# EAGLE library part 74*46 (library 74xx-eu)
BCD to seven segment DECODER/DRIVER, open collector

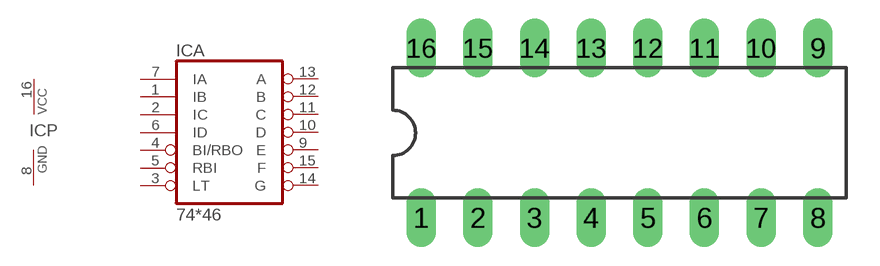
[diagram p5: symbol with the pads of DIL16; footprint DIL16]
Designator prefix IC; gates A=7446 P=PWRN

## 7446N  [DIL16]
1  A:IB  in
2  A:IC  in
3  A:LT  in
4  A:BI/RBO  in
5  A:RBI  in
6  A:ID  in
7  A:IA  in
8  P:GND  pwr
9  A:E  oc
10  A:D  oc
11  A:C  oc
12  A:B  oc
13  A:A  oc
14  A:G  oc
15  A:F  oc
16  P:VCC  pwr

## Footprint DIL16 (pad centres in mm)
Dual In Line Package
drill 0.813 long: 1 -8.89,-3.81; 2 -6.35,-3.81; 3 -3.81,-3.81; 4 -1.27,-3.81; 5 1.27,-3.81; 6 3.81,-3.81; 7 6.35,-3.81; 8 8.89,-3.81; 9 8.89,3.81; 10 6.35,3.81; 11 3.81,3.81; 12 1.27,3.81; 13 -1.27,3.81; 14 -3.81,3.81; 15 -6.35,3.81; 16 -8.89,3.81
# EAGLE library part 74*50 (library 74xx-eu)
Dual 2-wide 2-input AND OR INVERTER gate (one gate expandable)

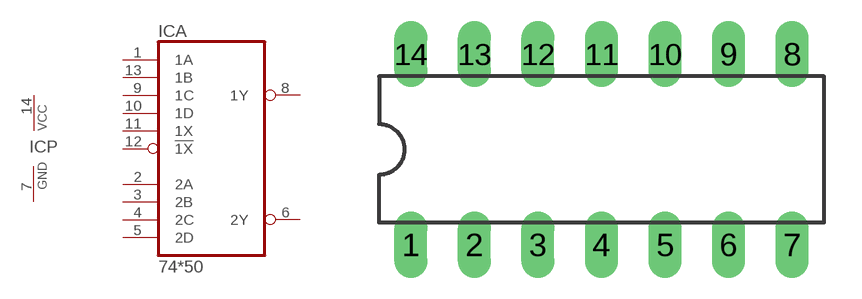
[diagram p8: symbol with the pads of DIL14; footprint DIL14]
Designator prefix IC; gates A=7450 P=PWRN

## 7450N  [DIL14]
1  A:1A  in
2  A:2A  in
3  A:2B  in
4  A:2C  in
5  A:2D  in
6  A:2Y  out
7  P:GND  pwr
8  A:1Y  out
9  A:1C  in
10  A:1D  in
11  A:1X  in
12  A:!1X  in
13  A:1B  in
14  P:VCC  pwr

## Footprint DIL14 (pad centres in mm)
Dual In Line Package
drill 0.813 long: 1 -7.62,-3.81; 2 -5.08,-3.81; 3 -2.54,-3.81; 4 0,-3.81; 5 2.54,-3.81; 6 5.08,-3.81; 7 7.62,-3.81; 8 7.62,3.81; 9 5.08,3.81; 10 2.54,3.81; 11 0,3.81; 12 -2.54,3.81; 13 -5.08,3.81; 14 -7.62,3.81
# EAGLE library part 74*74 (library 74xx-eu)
Dual D type positive edge triggered FLIP FLOP, preset and clear

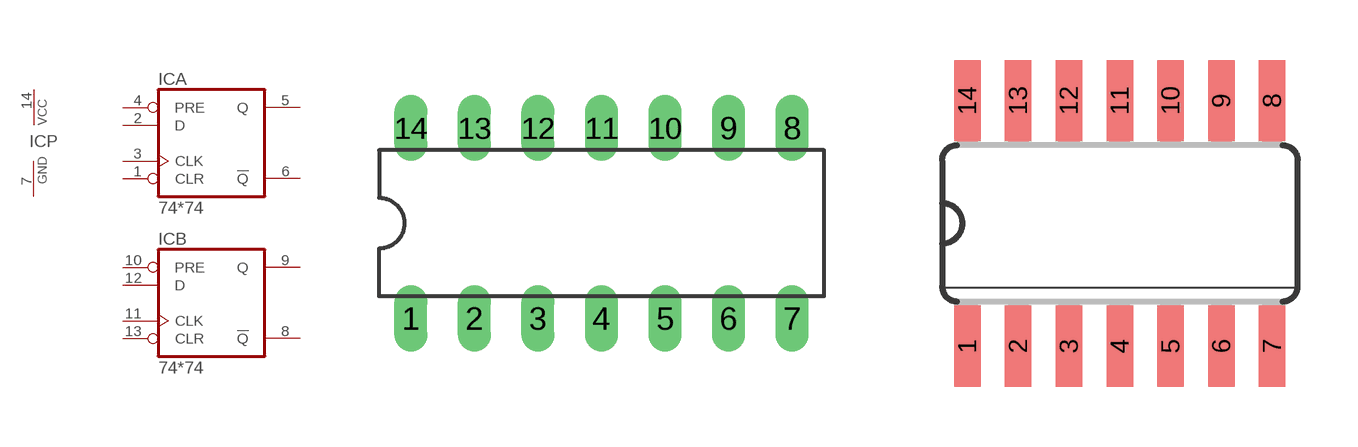
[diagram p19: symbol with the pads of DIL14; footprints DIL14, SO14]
Designator prefix IC; gates A=7474 B=7474 P=PWRN

## 74AC74N, 74ACT74N, 74HC74N, 74HCT74N, 74LS74N, 74S74N  [DIL14]
1  A:CLR  in
2  A:D  in
3  A:CLK  in
4  A:PRE  in
5  A:Q  out
6  A:!Q  out
7  P:GND  pwr
8  B:!Q  out
9  B:Q  out
10  B:PRE  in
11  B:CLK  in
12  B:D  in
13  B:CLR  in
14  P:VCC  pwr

## 74AC74D, 74ACT74D, 74HC74D, 74HCT74D, 74LS74D, 74S74D  [SO14]
Pads as for DIL14

## 74AC74FK, 74ACT74FK, 74HC74FK, 74HCT74FK, 74LS74FK, 74S74FK  [LCC20]
2  A:CLR  in
3  A:D  in
4  A:CLK  in
6  A:PRE  in
8  A:Q  out
9  A:!Q  out
10  P:GND  pwr
12  B:!Q  out
13  B:Q  out
14  B:PRE  in
16  B:CLK  in
18  B:D  in
19  B:CLR  in
20  P:VCC  pwr

## Footprint DIL14 (pad centres in mm)
Dual In Line Package
drill 0.813 long: 1 -7.62,-3.81; 2 -5.08,-3.81; 3 -2.54,-3.81; 4 0,-3.81; 5 2.54,-3.81; 6 5.08,-3.81; 7 7.62,-3.81; 8 7.62,3.81; 9 5.08,3.81; 10 2.54,3.81; 11 0,3.81; 12 -2.54,3.81; 13 -5.08,3.81; 14 -7.62,3.81

## Footprint SO14 (pad centres in mm)
Small Outline package 150 mil
smd 0.66 x 2.032: 1 -3.81,-3.073; 2 -2.54,-3.073; 3 -1.27,-3.073; 4 0,-3.073; 5 1.27,-3.073; 6 2.54,-3.073; 7 3.81,-3.073; 8 3.81,3.073; 9 2.54,3.073; 10 1.27,3.073; 11 0,3.073; 12 -1.27,3.073; 13 -2.54,3.073; 14 -3.81,3.073

## Footprint LCC20 (pad centres in mm)
Leadless Chip Carrier Ceramic Package
smd 0.8 x 3.4: 1 0,3.8
smd 0.8 x 2: 2 -1.27,4.5; 3 -2.54,4.5; 9 -2.54,-4.5; 10 -1.27,-4.5; 11 0,-4.5; 12 1.27,-4.5; 13 2.54,-4.5; 19 2.54,4.5; 20 1.27,4.5
smd 2 x 0.8: 4 -4.5,2.54; 5 -4.5,1.27; 6 -4.5,0; 7 -4.5,-1.27; 8 -4.5,-2.54; 14 4.5,-2.54; 15 4.5,-1.27; 16 4.5,0; 17 4.5,1.27; 18 4.5,2.54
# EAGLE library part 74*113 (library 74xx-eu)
Dual J-K negative edge triggered FLIP FLOP, preset

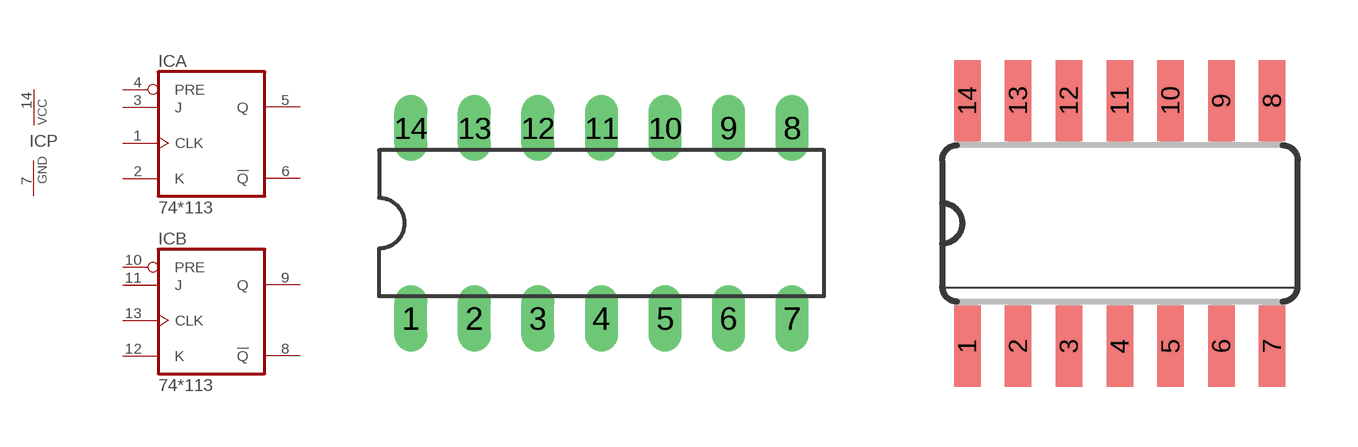
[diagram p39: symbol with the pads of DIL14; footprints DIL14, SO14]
Designator prefix IC; gates A=74113 B=74113 P=PWRN

## 74HC113N, 74HCT113N, 74LS113N, 74S113N  [DIL14]
1  A:CLK  in
2  A:K  in
3  A:J  in
4  A:PRE  in
5  A:Q  out
6  A:!Q  out
7  P:GND  pwr
8  B:!Q  out
9  B:Q  out
10  B:PRE  in
11  B:J  in
12  B:K  in
13  B:CLK  in
14  P:VCC  pwr

## 74HC113D, 74HCT113D, 74LS113D, 74S113D  [SO14]
Pads as for DIL14

## Footprint DIL14 (pad centres in mm)
Dual In Line Package
drill 0.813 long: 1 -7.62,-3.81; 2 -5.08,-3.81; 3 -2.54,-3.81; 4 0,-3.81; 5 2.54,-3.81; 6 5.08,-3.81; 7 7.62,-3.81; 8 7.62,3.81; 9 5.08,3.81; 10 2.54,3.81; 11 0,3.81; 12 -2.54,3.81; 13 -5.08,3.81; 14 -7.62,3.81

## Footprint SO14 (pad centres in mm)
Small Outline package 150 mil
smd 0.66 x 2.032: 1 -3.81,-3.073; 2 -2.54,-3.073; 3 -1.27,-3.073; 4 0,-3.073; 5 1.27,-3.073; 6 2.54,-3.073; 7 3.81,-3.073; 8 3.81,3.073; 9 2.54,3.073; 10 1.27,3.073; 11 0,3.073; 12 -1.27,3.073; 13 -2.54,3.073; 14 -3.81,3.073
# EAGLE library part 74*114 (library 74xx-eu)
Dual J-K negative edge triggered FLIP FLOP, preset, common clear, clock

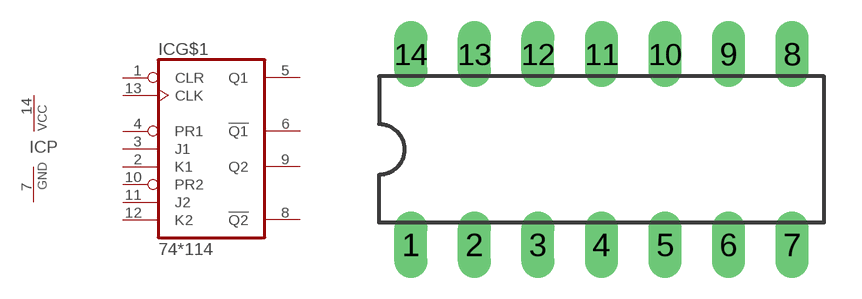
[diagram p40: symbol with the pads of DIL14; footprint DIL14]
Designator prefix IC; gates P=PWRN G$1=7478

## 74LS114N, 74S114N  [DIL14]
1  G$1:CLR  in
2  G$1:K1  in
3  G$1:J1  in
4  G$1:PR1  in
5  G$1:Q1  out
6  G$1:!Q1  out
7  P:GND  pwr
8  G$1:!Q2  out
9  G$1:Q2  out
10  G$1:PR2  in
11  G$1:J2  in
12  G$1:K2  in
13  G$1:CLK  in
14  P:VCC  pwr

## Footprint DIL14 (pad centres in mm)
Dual In Line Package
drill 0.813 long: 1 -7.62,-3.81; 2 -5.08,-3.81; 3 -2.54,-3.81; 4 0,-3.81; 5 2.54,-3.81; 6 5.08,-3.81; 7 7.62,-3.81; 8 7.62,3.81; 9 5.08,3.81; 10 2.54,3.81; 11 0,3.81; 12 -2.54,3.81; 13 -5.08,3.81; 14 -7.62,3.81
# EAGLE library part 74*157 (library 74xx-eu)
Quadruple 2-line to 1-line data SELECTOR/MULTIPLEXER

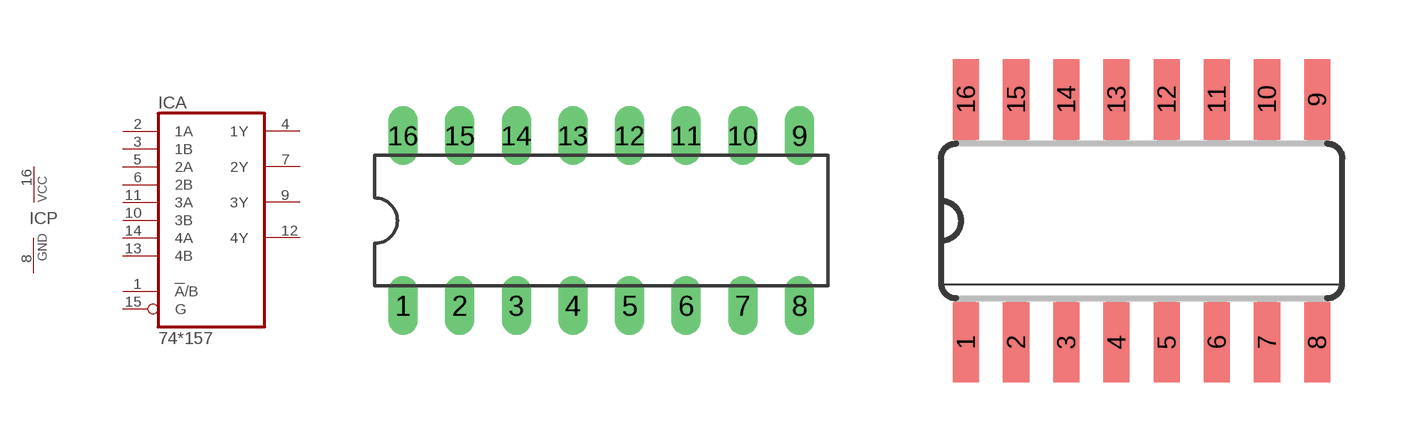
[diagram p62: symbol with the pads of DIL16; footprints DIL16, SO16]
Designator prefix IC; gates A=74157 P=PWRN

## 74157N, 74AC157N, 74ACT157N, 74HC157N, 74HCT157N, 74LS157N, 74S157N  [DIL16]
1  A:!A!/B  in
2  A:1A  in
3  A:1B  in
4  A:1Y  out
5  A:2A  in
6  A:2B  in
7  A:2Y  out
8  P:GND  pwr
9  A:3Y  out
10  A:3B  in
11  A:3A  in
12  A:4Y  out
13  A:4B  in
14  A:4A  in
15  A:G  in
16  P:VCC  pwr

## 74157D, 74AC157D, 74ACT157D, 74HC157D, 74HCT157D, 74LS157D, 74S157D  [SO16]
Pads as for DIL16

## 74AC157FK, 74ACT157FK, 74HC157FK, 74HCT157FK, 74LS157FK, 74S157FK  [LCC20]
2  A:!A!/B  in
3  A:1A  in
4  A:1B  in
5  A:1Y  out
7  A:2A  in
8  A:2B  in
9  A:2Y  out
10  P:GND  pwr
12  A:3Y  out
13  A:3B  in
14  A:3A  in
15  A:4Y  out
17  A:4B  in
18  A:4A  in
19  A:G  in
20  P:VCC  pwr

## Footprint DIL16 (pad centres in mm)
Dual In Line Package
drill 0.813 long: 1 -8.89,-3.81; 2 -6.35,-3.81; 3 -3.81,-3.81; 4 -1.27,-3.81; 5 1.27,-3.81; 6 3.81,-3.81; 7 6.35,-3.81; 8 8.89,-3.81; 9 8.89,3.81; 10 6.35,3.81; 11 3.81,3.81; 12 1.27,3.81; 13 -1.27,3.81; 14 -3.81,3.81; 15 -6.35,3.81; 16 -8.89,3.81

## Footprint SO16 (pad centres in mm)
Small Outline package 150 mil
smd 0.66 x 2.032: 1 -4.445,-3.073; 2 -3.175,-3.073; 3 -1.905,-3.073; 4 -0.635,-3.073; 5 0.635,-3.073; 6 1.905,-3.073; 7 3.175,-3.073; 8 4.445,-3.073; 9 4.445,3.073; 10 3.175,3.073; 11 1.905,3.073; 12 0.635,3.073; 13 -0.635,3.073; 14 -1.905,3.073; 15 -3.175,3.073; 16 -4.445,3.073

## Footprint LCC20 (pad centres in mm)
Leadless Chip Carrier Ceramic Package
smd 0.8 x 3.4: 1 0,3.8
smd 0.8 x 2: 2 -1.27,4.5; 3 -2.54,4.5; 9 -2.54,-4.5; 10 -1.27,-4.5; 11 0,-4.5; 12 1.27,-4.5; 13 2.54,-4.5; 19 2.54,4.5; 20 1.27,4.5
smd 2 x 0.8: 4 -4.5,2.54; 5 -4.5,1.27; 6 -4.5,0; 7 -4.5,-1.27; 8 -4.5,-2.54; 14 4.5,-2.54; 15 4.5,-1.27; 16 4.5,0; 17 4.5,1.27; 18 4.5,2.54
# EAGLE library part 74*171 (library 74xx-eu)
Quadruple D type FLIP FLOP, clear

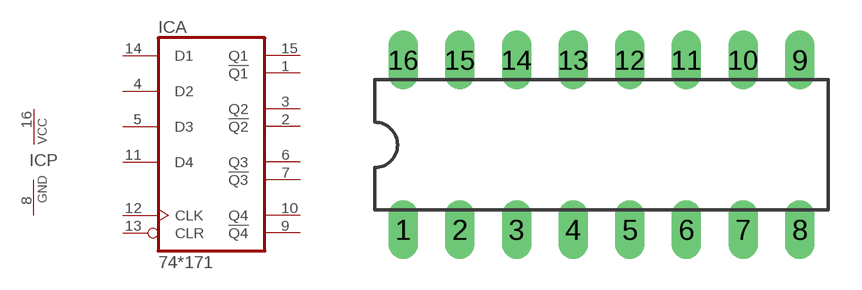
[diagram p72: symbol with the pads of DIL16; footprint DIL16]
Designator prefix IC; gates A=74171 P=PWRN

## 74LS171N  [DIL16]
1  A:!Q1  out
2  A:!Q2  out
3  A:Q2  out
4  A:D2  in
5  A:D3  in
6  A:Q3  out
7  A:!Q3  out
8  P:GND  pwr
9  A:!Q4  out
10  A:Q4  out
11  A:D4  in
12  A:CLK  in
13  A:CLR  in
14  A:D1  in
15  A:Q1  out
16  P:VCC  pwr

## Footprint DIL16 (pad centres in mm)
Dual In Line Package
drill 0.813 long: 1 -8.89,-3.81; 2 -6.35,-3.81; 3 -3.81,-3.81; 4 -1.27,-3.81; 5 1.27,-3.81; 6 3.81,-3.81; 7 6.35,-3.81; 8 8.89,-3.81; 9 8.89,3.81; 10 6.35,3.81; 11 3.81,3.81; 12 1.27,3.81; 13 -1.27,3.81; 14 -3.81,3.81; 15 -6.35,3.81; 16 -8.89,3.81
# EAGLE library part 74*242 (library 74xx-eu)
Quadruple BUS TRANSCEIVER

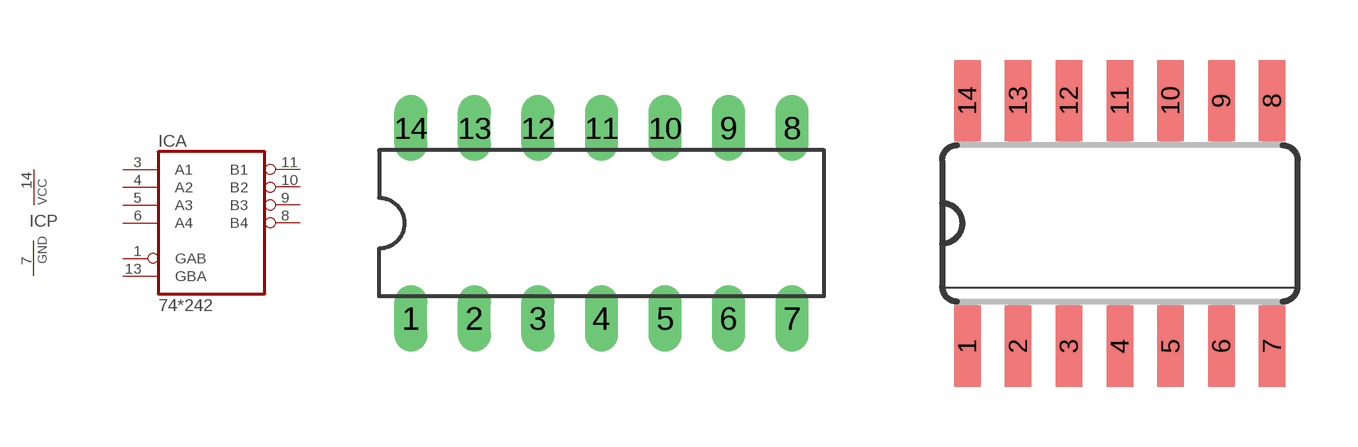
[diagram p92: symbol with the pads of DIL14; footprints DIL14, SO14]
Designator prefix IC; gates A=74242 P=PWRN

## 74242N, 74HC242N, 74HCT242N  [DIL14]
1  A:GAB  in
3  A:A1
4  A:A2
5  A:A3
6  A:A4
7  P:GND  pwr
8  A:B4
9  A:B3
10  A:B2
11  A:B1
13  A:GBA  in
14  P:VCC  pwr

## 74HC242D, 74HCT242D  [SO14]
Pads as for DIL14

## Footprint DIL14 (pad centres in mm)
Dual In Line Package
drill 0.813 long: 1 -7.62,-3.81; 2 -5.08,-3.81; 3 -2.54,-3.81; 4 0,-3.81; 5 2.54,-3.81; 6 5.08,-3.81; 7 7.62,-3.81; 8 7.62,3.81; 9 5.08,3.81; 10 2.54,3.81; 11 0,3.81; 12 -2.54,3.81; 13 -5.08,3.81; 14 -7.62,3.81

## Footprint SO14 (pad centres in mm)
Small Outline package 150 mil
smd 0.66 x 2.032: 1 -3.81,-3.073; 2 -2.54,-3.073; 3 -1.27,-3.073; 4 0,-3.073; 5 1.27,-3.073; 6 2.54,-3.073; 7 3.81,-3.073; 8 3.81,3.073; 9 2.54,3.073; 10 1.27,3.073; 11 0,3.073; 12 -1.27,3.073; 13 -2.54,3.073; 14 -3.81,3.073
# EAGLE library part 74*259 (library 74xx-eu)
8-bit addressable LATCH

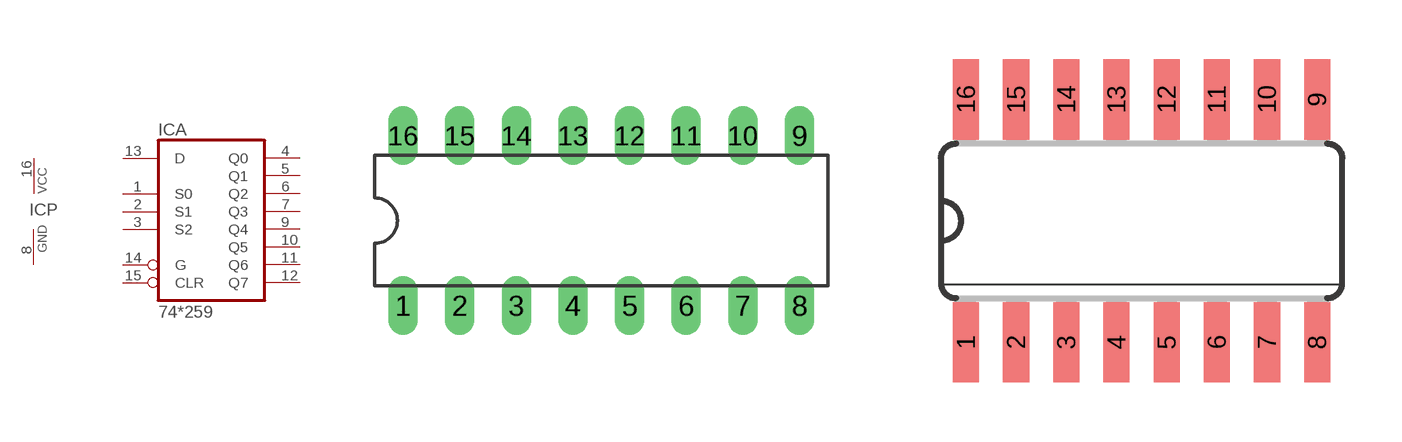
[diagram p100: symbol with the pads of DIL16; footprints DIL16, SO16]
Designator prefix IC; gates A=74259 P=PWRN

## 74259N, 74AC259N, 74ACT259N, 74HC259N, 74HCT259N, 74LS259N  [DIL16]
1  A:S0  in
2  A:S1  in
3  A:S2  in
4  A:Q0  out
5  A:Q1  out
6  A:Q2  out
7  A:Q3  out
8  P:GND  pwr
9  A:Q4  out
10  A:Q5  out
11  A:Q6  out
12  A:Q7  out
13  A:D  in
14  A:G  in
15  A:CLR  in
16  P:VCC  pwr

## 74259D, 74AC259D, 74ACT259D, 74HC259D, 74HCT259D  [SO16]
Pads as for DIL16

## Footprint DIL16 (pad centres in mm)
Dual In Line Package
drill 0.813 long: 1 -8.89,-3.81; 2 -6.35,-3.81; 3 -3.81,-3.81; 4 -1.27,-3.81; 5 1.27,-3.81; 6 3.81,-3.81; 7 6.35,-3.81; 8 8.89,-3.81; 9 8.89,3.81; 10 6.35,3.81; 11 3.81,3.81; 12 1.27,3.81; 13 -1.27,3.81; 14 -3.81,3.81; 15 -6.35,3.81; 16 -8.89,3.81

## Footprint SO16 (pad centres in mm)
Small Outline package 150 mil
smd 0.66 x 2.032: 1 -4.445,-3.073; 2 -3.175,-3.073; 3 -1.905,-3.073; 4 -0.635,-3.073; 5 0.635,-3.073; 6 1.905,-3.073; 7 3.175,-3.073; 8 4.445,-3.073; 9 4.445,3.073; 10 3.175,3.073; 11 1.905,3.073; 12 0.635,3.073; 13 -0.635,3.073; 14 -1.905,3.073; 15 -3.175,3.073; 16 -4.445,3.073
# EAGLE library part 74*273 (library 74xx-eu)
Octal D type FLIP FLOP, clear

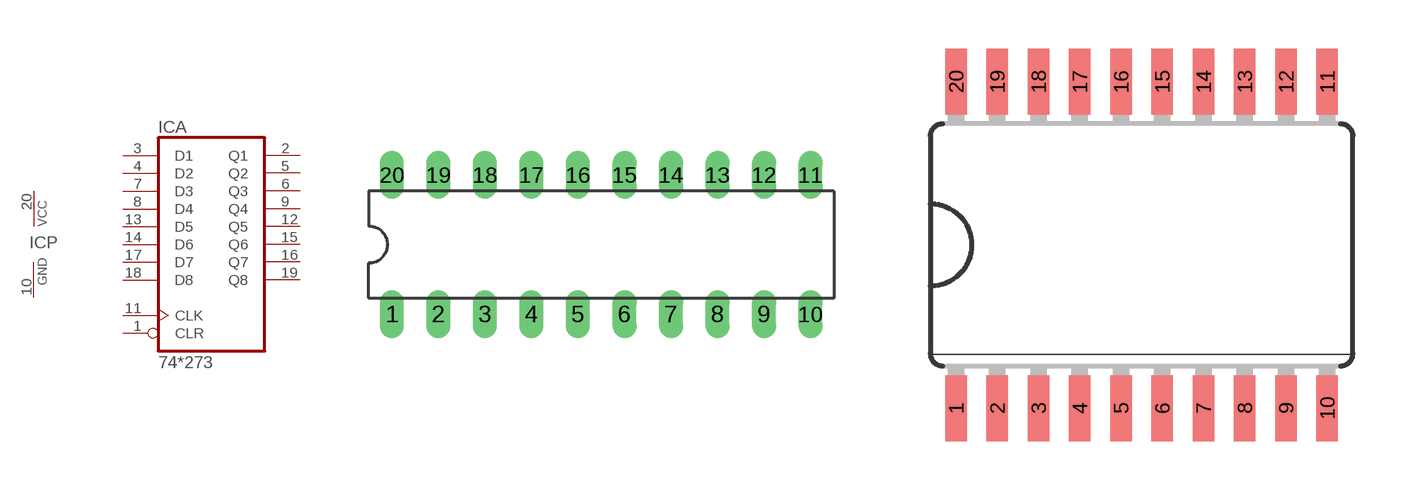
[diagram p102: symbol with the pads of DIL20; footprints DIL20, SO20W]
Designator prefix IC; gates A=74273 P=PWRN

## 74273N, 74AC273N, 74ACT273N, 74HC273N, 74HCT273N  [DIL20]
1  A:CLR  in
2  A:Q1  out
3  A:D1  in
4  A:D2  in
5  A:Q2  out
6  A:Q3  out
7  A:D3  in
8  A:D4  in
9  A:Q4  out
10  P:GND  pwr
11  A:CLK  in
12  A:Q5  out
13  A:D5  in
14  A:D6  in
15  A:Q6  out
16  A:Q7  out
17  A:D7  in
18  A:D8  in
19  A:Q8  out
20  P:VCC  pwr

## 74AC273DW, 74ACT273DW, 74HC273DW, 74HCT273DW, 74LS273DW  [SO20W]
Pads as for DIL20

## 74AC273FK, 74ACT273FK, 74HC273FK, 74HCT273FK, 74LS273FK  [LCC20]
Pads as for DIL20

## Footprint DIL20 (pad centres in mm)
Dual In Line Package
drill 0.813 long: 1 -11.43,-3.81; 2 -8.89,-3.81; 3 -6.35,-3.81; 4 -3.81,-3.81; 5 -1.27,-3.81; 6 1.27,-3.81; 7 3.81,-3.81; 8 6.35,-3.81; 9 8.89,-3.81; 10 11.43,-3.81; 11 11.43,3.81; 12 8.89,3.81; 13 6.35,3.81; 14 3.81,3.81; 15 1.27,3.81; 16 -1.27,3.81; 17 -3.81,3.81; 18 -6.35,3.81; 19 -8.89,3.81; 20 -11.43,3.81

## Footprint SO20W (pad centres in mm)
Wide Small Outline package 300 mil
smd 0.66 x 2.032: 1 -5.715,-5.029; 2 -4.445,-5.029; 3 -3.175,-5.029; 4 -1.905,-5.029; 5 -0.635,-5.029; 6 0.635,-5.029; 7 1.905,-5.029; 8 3.175,-5.029; 9 4.445,-5.029; 10 5.715,-5.029; 11 5.715,5.029; 12 4.445,5.029; 13 3.175,5.029; 14 1.905,5.029; 15 0.635,5.029; 16 -0.635,5.029; 17 -1.905,5.029; 18 -3.175,5.029; 19 -4.445,5.029; 20 -5.715,5.029

## Footprint LCC20 (pad centres in mm)
Leadless Chip Carrier Ceramic Package
smd 0.8 x 3.4: 1 0,3.8
smd 0.8 x 2: 2 -1.27,4.5; 3 -2.54,4.5; 9 -2.54,-4.5; 10 -1.27,-4.5; 11 0,-4.5; 12 1.27,-4.5; 13 2.54,-4.5; 19 2.54,4.5; 20 1.27,4.5
smd 2 x 0.8: 4 -4.5,2.54; 5 -4.5,1.27; 6 -4.5,0; 7 -4.5,-1.27; 8 -4.5,-2.54; 14 4.5,-2.54; 15 4.5,-1.27; 16 4.5,0; 17 4.5,1.27; 18 4.5,2.54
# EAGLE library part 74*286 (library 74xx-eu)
9-bit PARITY GENERATOR/CHECKER

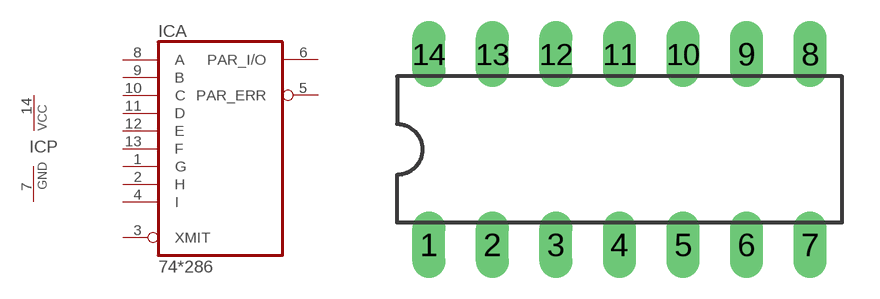
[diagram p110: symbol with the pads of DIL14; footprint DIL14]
Designator prefix IC; gates A=74286 P=PWRN

## 74286N  [DIL14]
1  A:G  in
2  A:H  in
3  A:XMIT  in
4  A:I  in
5  A:PAR_ERR  out
6  A:PAR_I/O
7  P:GND  pwr
8  A:A  in
9  A:B  in
10  A:C  in
11  A:D  in
12  A:E  in
13  A:F  in
14  P:VCC  pwr

## Footprint DIL14 (pad centres in mm)
Dual In Line Package
drill 0.813 long: 1 -7.62,-3.81; 2 -5.08,-3.81; 3 -2.54,-3.81; 4 0,-3.81; 5 2.54,-3.81; 6 5.08,-3.81; 7 7.62,-3.81; 8 7.62,3.81; 9 5.08,3.81; 10 2.54,3.81; 11 0,3.81; 12 -2.54,3.81; 13 -5.08,3.81; 14 -7.62,3.81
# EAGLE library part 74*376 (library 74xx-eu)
Quadruple J-K FLIP FLOP

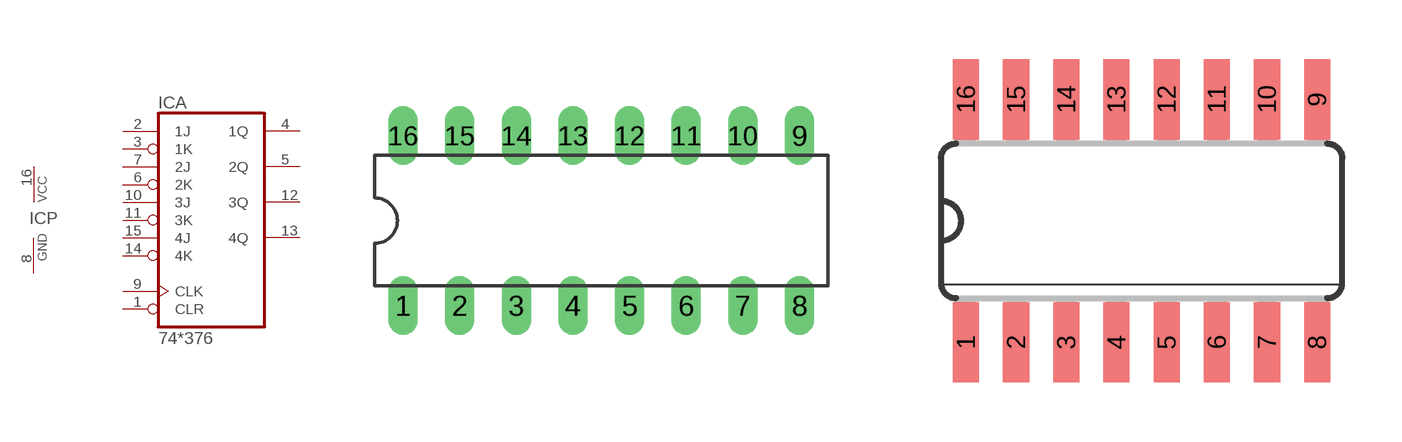
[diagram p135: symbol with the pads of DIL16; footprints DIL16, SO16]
Designator prefix IC; gates A=74376 P=PWRN

## 74376N  [DIL16]
1  A:CLR  in
2  A:1J  in
3  A:1K  in
4  A:1Q  out
5  A:2Q  out
6  A:2K  in
7  A:2J  in
8  P:GND  pwr
9  A:CLK  in
10  A:3J  in
11  A:3K  in
12  A:3Q  out
13  A:4Q  out
14  A:4K  in
15  A:4J  in
16  P:VCC  pwr

## 74376D  [SO16]
Pads as for DIL16

## Footprint DIL16 (pad centres in mm)
Dual In Line Package
drill 0.813 long: 1 -8.89,-3.81; 2 -6.35,-3.81; 3 -3.81,-3.81; 4 -1.27,-3.81; 5 1.27,-3.81; 6 3.81,-3.81; 7 6.35,-3.81; 8 8.89,-3.81; 9 8.89,3.81; 10 6.35,3.81; 11 3.81,3.81; 12 1.27,3.81; 13 -1.27,3.81; 14 -3.81,3.81; 15 -6.35,3.81; 16 -8.89,3.81

## Footprint SO16 (pad centres in mm)
Small Outline package 150 mil
smd 0.66 x 2.032: 1 -4.445,-3.073; 2 -3.175,-3.073; 3 -1.905,-3.073; 4 -0.635,-3.073; 5 0.635,-3.073; 6 1.905,-3.073; 7 3.175,-3.073; 8 4.445,-3.073; 9 4.445,3.073; 10 3.175,3.073; 11 1.905,3.073; 12 0.635,3.073; 13 -0.635,3.073; 14 -1.905,3.073; 15 -3.175,3.073; 16 -4.445,3.073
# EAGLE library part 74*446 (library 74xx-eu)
Quadruple BUS TRANSCEIVER

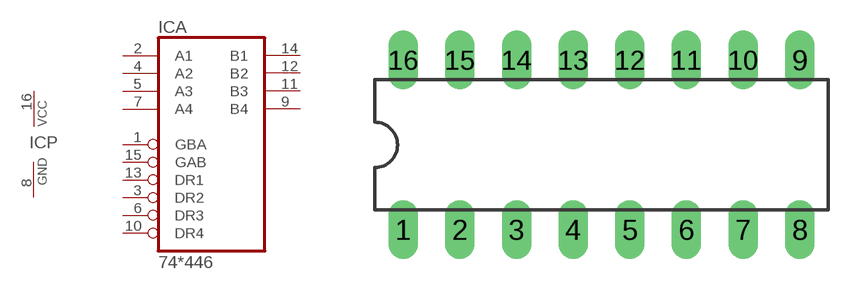
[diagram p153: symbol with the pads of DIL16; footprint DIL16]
Designator prefix IC; gates A=74446 P=PWRN

## 74446N  [DIL16]
1  A:GBA  in
2  A:A1
3  A:DR2  in
4  A:A2
5  A:A3
6  A:DR3  in
7  A:A4
8  P:GND  pwr
9  A:B4
10  A:DR4  in
11  A:B3
12  A:B2
13  A:DR1  in
14  A:B1
15  A:GAB  in
16  P:VCC  pwr

## Footprint DIL16 (pad centres in mm)
Dual In Line Package
drill 0.813 long: 1 -8.89,-3.81; 2 -6.35,-3.81; 3 -3.81,-3.81; 4 -1.27,-3.81; 5 1.27,-3.81; 6 3.81,-3.81; 7 6.35,-3.81; 8 8.89,-3.81; 9 8.89,3.81; 10 6.35,3.81; 11 3.81,3.81; 12 1.27,3.81; 13 -1.27,3.81; 14 -3.81,3.81; 15 -6.35,3.81; 16 -8.89,3.81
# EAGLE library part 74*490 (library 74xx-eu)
Dual 4-bit decade COUNTER

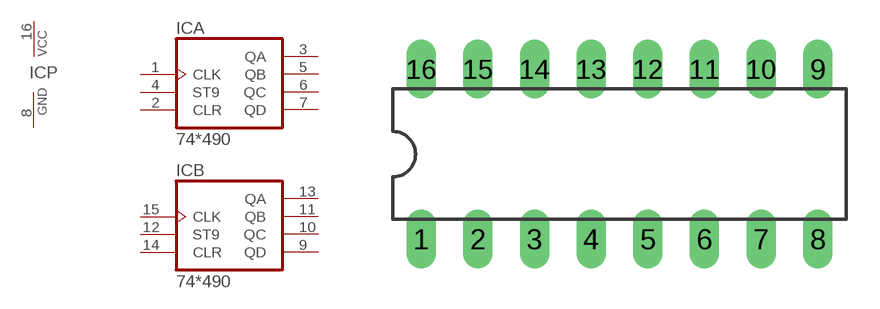
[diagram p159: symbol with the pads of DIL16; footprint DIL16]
Designator prefix IC; gates A=74490 B=74490 P=PWRN

## 74490N  [DIL16]
1  A:CLK  in
2  A:CLR  in
3  A:QA  out
4  A:ST9  in
5  A:QB  out
6  A:QC  out
7  A:QD  out
8  P:GND  pwr
9  B:QD  out
10  B:QC  out
11  B:QB  out
12  B:ST9  in
13  B:QA  out
14  B:CLR  in
15  B:CLK  in
16  P:VCC  pwr

## Footprint DIL16 (pad centres in mm)
Dual In Line Package
drill 0.813 long: 1 -8.89,-3.81; 2 -6.35,-3.81; 3 -3.81,-3.81; 4 -1.27,-3.81; 5 1.27,-3.81; 6 3.81,-3.81; 7 6.35,-3.81; 8 8.89,-3.81; 9 8.89,3.81; 10 6.35,3.81; 11 3.81,3.81; 12 1.27,3.81; 13 -1.27,3.81; 14 -3.81,3.81; 15 -6.35,3.81; 16 -8.89,3.81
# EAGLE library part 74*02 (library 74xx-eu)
Quad 2-input NOR gate

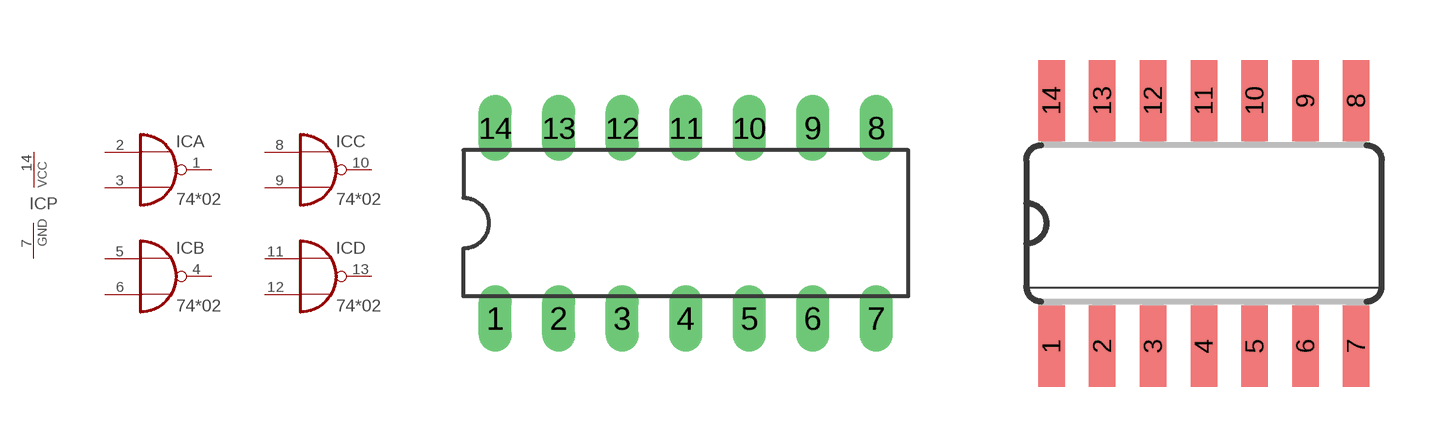
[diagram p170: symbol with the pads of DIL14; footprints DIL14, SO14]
Designator prefix IC; gates A=7402 B=7402 C=7402 D=7402 P=PWRN

## 7402N, 74AC02N, 74ACT02N, 74ALS02N, 74AS02N, 74HC02N, 74HCT02N, 74LS02N, 74S02N  [DIL14]
1  A:O  out
2  A:I0  in
3  A:I1  in
4  B:O  out
5  B:I0  in
6  B:I1  in
7  P:GND  pwr
8  C:I0  in
9  C:I1  in
10  C:O  out
11  D:I0  in
12  D:I1  in
13  D:O  out
14  P:VCC  pwr

## 7402D, 74AC02D, 74ACT02D, 74ALS02D, 74AS02D, 74HC02D, 74HCT02D, 74LS02D, 74S02D  [SO14]
Pads as for DIL14

## 7402FK, 74AC02FK, 74ACT02FK, 74ALS02FK, 74AS02FK, 74HC02FK, 74HCT02FK, 74LS02FK, 74S02FK  [LCC20]
2  A:O  out
3  A:I0  in
4  A:I1  in
6  B:O  out
8  B:I0  in
9  B:I1  in
10  P:GND  pwr
12  C:I0  in
13  C:I1  in
14  C:O  out
16  D:I0  in
18  D:I1  in
19  D:O  out
20  P:VCC  pwr

## Footprint DIL14 (pad centres in mm)
Dual In Line Package
drill 0.813 long: 1 -7.62,-3.81; 2 -5.08,-3.81; 3 -2.54,-3.81; 4 0,-3.81; 5 2.54,-3.81; 6 5.08,-3.81; 7 7.62,-3.81; 8 7.62,3.81; 9 5.08,3.81; 10 2.54,3.81; 11 0,3.81; 12 -2.54,3.81; 13 -5.08,3.81; 14 -7.62,3.81

## Footprint SO14 (pad centres in mm)
Small Outline package 150 mil
smd 0.66 x 2.032: 1 -3.81,-3.073; 2 -2.54,-3.073; 3 -1.27,-3.073; 4 0,-3.073; 5 1.27,-3.073; 6 2.54,-3.073; 7 3.81,-3.073; 8 3.81,3.073; 9 2.54,3.073; 10 1.27,3.073; 11 0,3.073; 12 -1.27,3.073; 13 -2.54,3.073; 14 -3.81,3.073

## Footprint LCC20 (pad centres in mm)
Leadless Chip Carrier Ceramic Package
smd 0.8 x 3.4: 1 0,3.8
smd 0.8 x 2: 2 -1.27,4.5; 3 -2.54,4.5; 9 -2.54,-4.5; 10 -1.27,-4.5; 11 0,-4.5; 12 1.27,-4.5; 13 2.54,-4.5; 19 2.54,4.5; 20 1.27,4.5
smd 2 x 0.8: 4 -4.5,2.54; 5 -4.5,1.27; 6 -4.5,0; 7 -4.5,-1.27; 8 -4.5,-2.54; 14 4.5,-2.54; 15 4.5,-1.27; 16 4.5,0; 17 4.5,1.27; 18 4.5,2.54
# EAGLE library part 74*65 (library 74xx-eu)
4-2-3-2 input AND OR INVERTER gates

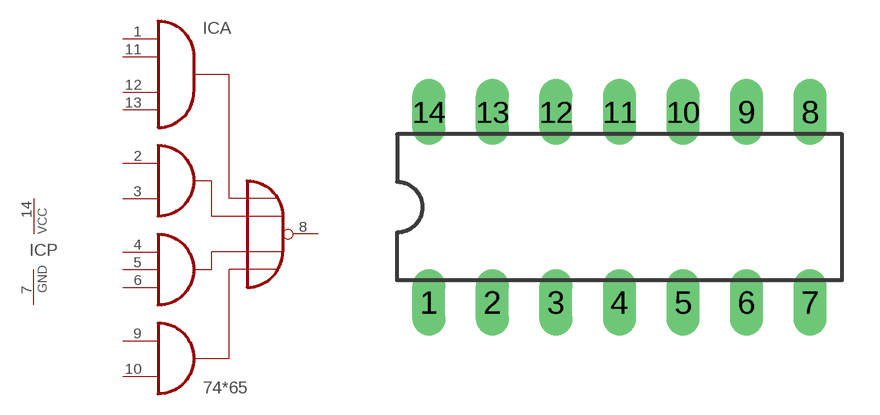
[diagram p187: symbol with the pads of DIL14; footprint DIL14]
Designator prefix IC; gates A=7465 P=PWRN

## 74S65N  [DIL14]
1  A:I0  in
2  A:I4  in
3  A:I5  in
4  A:I6  in
5  A:I7  in
6  A:I8  in
7  P:GND  pwr
8  A:O  oc
9  A:I9  in
10  A:I10  in
11  A:I1  in
12  A:I2  in
13  A:I3  in
14  P:VCC  pwr

## Footprint DIL14 (pad centres in mm)
Dual In Line Package
drill 0.813 long: 1 -7.62,-3.81; 2 -5.08,-3.81; 3 -2.54,-3.81; 4 0,-3.81; 5 2.54,-3.81; 6 5.08,-3.81; 7 7.62,-3.81; 8 7.62,3.81; 9 5.08,3.81; 10 2.54,3.81; 11 0,3.81; 12 -2.54,3.81; 13 -5.08,3.81; 14 -7.62,3.81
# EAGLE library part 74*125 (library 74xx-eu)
Quad bus BUFFER, 3-state

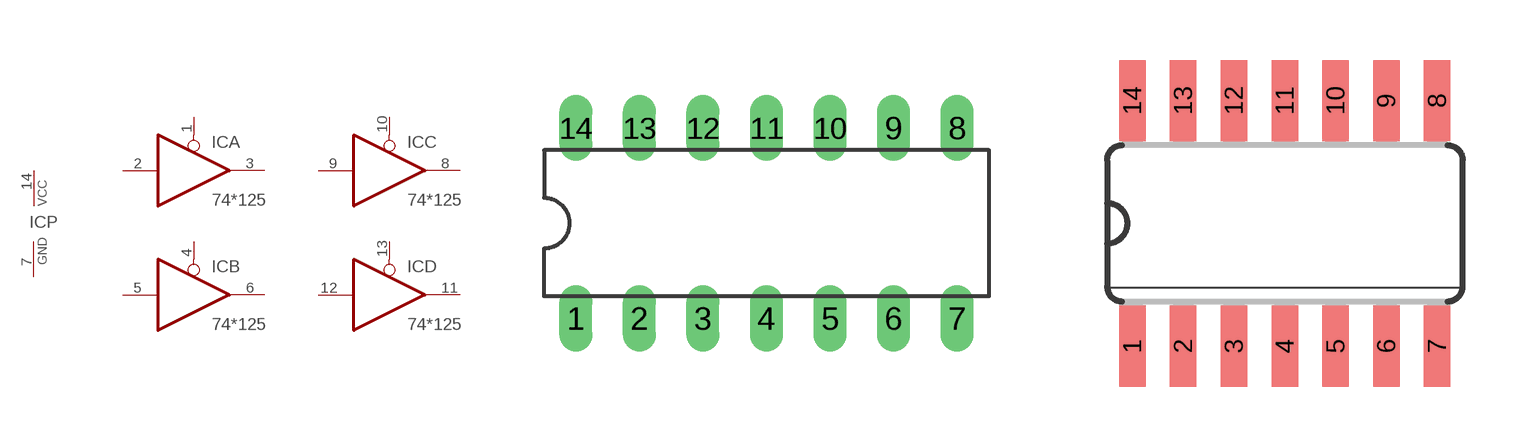
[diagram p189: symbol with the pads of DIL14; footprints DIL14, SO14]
Designator prefix IC; gates A=74125 B=74125 C=74125 D=74125 P=PWRN

## 74125N, 74AC125N, 74ACT125N, 74HC125N, 74HCT125N, 74LS125N  [DIL14]
1  A:OE  in
2  A:I  in
3  A:O  hiz
4  B:OE  in
5  B:I  in
6  B:O  hiz
7  P:GND  pwr
8  C:O  hiz
9  C:I  in
10  C:OE  in
11  D:O  hiz
12  D:I  in
13  D:OE  in
14  P:VCC  pwr

## 74AC125D, 74ACT125D, 74HC125D, 74HCT125D, 74LS125D  [SO14]
Pads as for DIL14

## 74ABT125DB  [SSOP14]
Pads as for DIL14

## 74ABT125PW  [TSSOP14]
Pads as for DIL14

## 74ABT125BQ  [DHVQFN14]
Pads as for DIL14

## Footprint DIL14 (pad centres in mm)
Dual In Line Package
drill 0.813 long: 1 -7.62,-3.81; 2 -5.08,-3.81; 3 -2.54,-3.81; 4 0,-3.81; 5 2.54,-3.81; 6 5.08,-3.81; 7 7.62,-3.81; 8 7.62,3.81; 9 5.08,3.81; 10 2.54,3.81; 11 0,3.81; 12 -2.54,3.81; 13 -5.08,3.81; 14 -7.62,3.81

## Footprint SO14 (pad centres in mm)
Small Outline package 150 mil
smd 0.66 x 2.032: 1 -3.81,-3.073; 2 -2.54,-3.073; 3 -1.27,-3.073; 4 0,-3.073; 5 1.27,-3.073; 6 2.54,-3.073; 7 3.81,-3.073; 8 3.81,3.073; 9 2.54,3.073; 10 1.27,3.073; 11 0,3.073; 12 -1.27,3.073; 13 -2.54,3.073; 14 -3.81,3.073

## Footprint SSOP14 (pad centres in mm)
plastic shrink small outline package; 14 leads; body width 5.3 mm SOT337-1 Source: http://www.nxp.com/documents/data_sheet/74ABT125.pdf
smd 0.4 x 1.1: 1 -1.95,-3.475; 2 -1.3,-3.475; 3 -0.65,-3.475; 4 0,-3.475; 5 0.65,-3.475; 6 1.3,-3.475; 7 1.95,-3.475; 8 1.95,3.475; 9 1.3,3.475; 10 0.65,3.475; 11 0,3.475; 12 -0.65,3.475; 13 -1.3,3.475; 14 -1.95,3.475

## Footprint TSSOP14 (pad centres in mm)
plastic thin shrink small outline package; 14 leads; body width 4.4 mm SOT402-1 Source: http://www.nxp.com/documents/data_sheet/74ABT125.pdf
smd 0.35 x 0.9: 1 -1.95,-2.925; 2 -1.3,-2.925; 3 -0.65,-2.925; 4 0,-2.925; 5 0.65,-2.925; 6 1.3,-2.925; 7 1.95,-2.925; 8 1.95,2.925; 9 1.3,2.925; 10 0.65,2.925; 11 0,2.925; 12 -0.65,2.925; 13 -1.3,2.925; 14 -1.95,2.925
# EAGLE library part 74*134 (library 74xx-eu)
12-input NAND gate, 3-stage

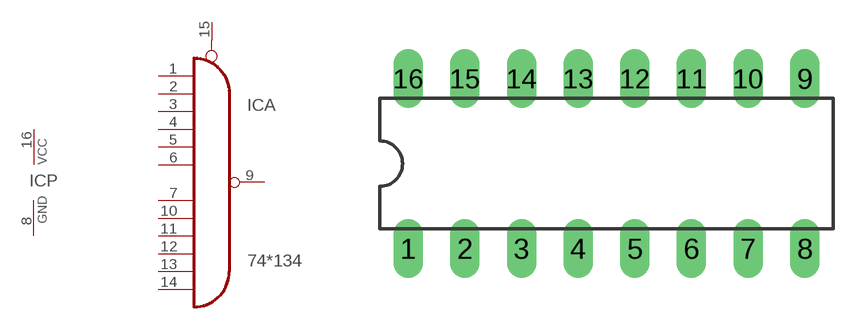
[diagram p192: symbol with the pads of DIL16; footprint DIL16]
Designator prefix IC; gates A=74134 P=PWRN

## 74S134N  [DIL16]
1  A:I0  in
2  A:I1  in
3  A:I2  in
4  A:I3  in
5  A:I4  in
6  A:I5  in
7  A:I6  in
8  P:GND  pwr
9  A:O  out
10  A:I7  in
11  A:I8  in
12  A:I9  in
13  A:I10  in
14  A:I11  in
15  A:OE  in
16  P:VCC  pwr

## Footprint DIL16 (pad centres in mm)
Dual In Line Package
drill 0.813 long: 1 -8.89,-3.81; 2 -6.35,-3.81; 3 -3.81,-3.81; 4 -1.27,-3.81; 5 1.27,-3.81; 6 3.81,-3.81; 7 6.35,-3.81; 8 8.89,-3.81; 9 8.89,3.81; 10 6.35,3.81; 11 3.81,3.81; 12 1.27,3.81; 13 -1.27,3.81; 14 -3.81,3.81; 15 -6.35,3.81; 16 -8.89,3.81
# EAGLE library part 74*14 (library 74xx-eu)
Hex schmitt trigger INVERTER

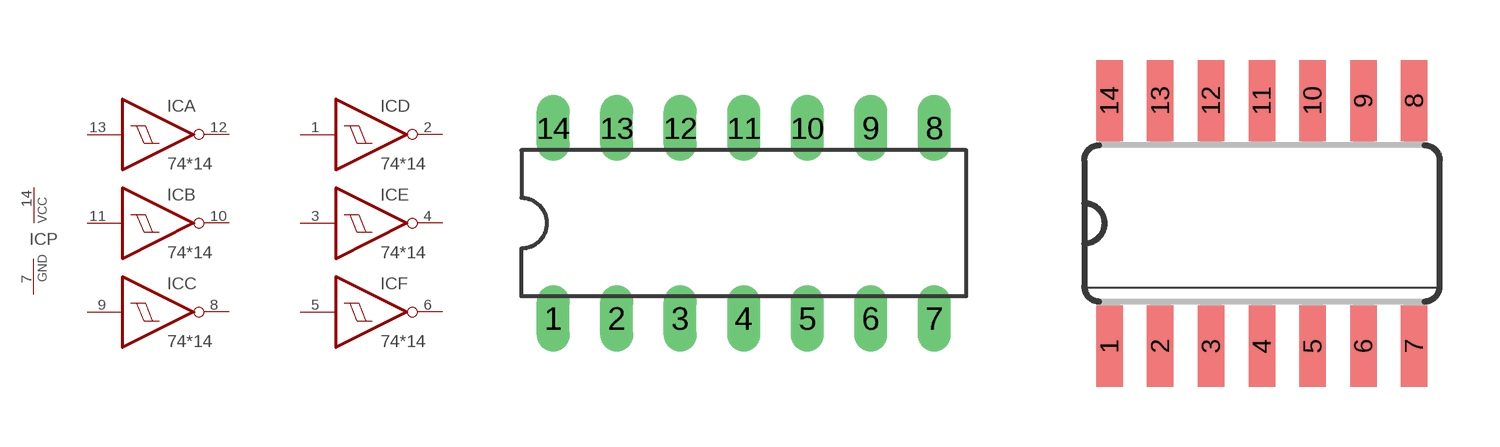
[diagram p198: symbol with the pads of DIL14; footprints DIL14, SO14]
Designator prefix IC; gates A=7414 B=7414 C=7414 D=7414 E=7414 F=7414 P=PWRN

## 7414N, 74AC14N, 74ACT14N, 74HC14N, 74HCT14N, 74LS14N  [DIL14]
1  D:I  in
2  D:O  out
3  E:I  in
4  E:O  out
5  F:I  in
6  F:O  out
7  P:GND  pwr
8  C:O  out
9  C:I  in
10  B:O  out
11  B:I  in
12  A:O  out
13  A:I  in
14  P:VCC  pwr

## 7414D, 74AC14D, 74ACT14D, 74HC14D, 74HCT14D, 74LS14D  [SO14]
Pads as for DIL14

## 7414FK, 74AC14FK, 74ACT14FK, 74HC14FK, 74HCT14FK, 74LS14FK  [LCC20]
2  A:I  in
3  A:O  out
4  B:I  in
6  B:O  out
8  C:I  in
9  C:O  out
10  P:GND  pwr
12  D:O  out
13  D:I  in
14  E:O  out
16  E:I  in
18  F:O  out
19  F:I  in
20  P:VCC  pwr

## Footprint DIL14 (pad centres in mm)
Dual In Line Package
drill 0.813 long: 1 -7.62,-3.81; 2 -5.08,-3.81; 3 -2.54,-3.81; 4 0,-3.81; 5 2.54,-3.81; 6 5.08,-3.81; 7 7.62,-3.81; 8 7.62,3.81; 9 5.08,3.81; 10 2.54,3.81; 11 0,3.81; 12 -2.54,3.81; 13 -5.08,3.81; 14 -7.62,3.81

## Footprint SO14 (pad centres in mm)
Small Outline package 150 mil
smd 0.66 x 2.032: 1 -3.81,-3.073; 2 -2.54,-3.073; 3 -1.27,-3.073; 4 0,-3.073; 5 1.27,-3.073; 6 2.54,-3.073; 7 3.81,-3.073; 8 3.81,3.073; 9 2.54,3.073; 10 1.27,3.073; 11 0,3.073; 12 -1.27,3.073; 13 -2.54,3.073; 14 -3.81,3.073

## Footprint LCC20 (pad centres in mm)
Leadless Chip Carrier Ceramic Package
smd 0.8 x 3.4: 1 0,3.8
smd 0.8 x 2: 2 -1.27,4.5; 3 -2.54,4.5; 9 -2.54,-4.5; 10 -1.27,-4.5; 11 0,-4.5; 12 1.27,-4.5; 13 2.54,-4.5; 19 2.54,4.5; 20 1.27,4.5
smd 2 x 0.8: 4 -4.5,2.54; 5 -4.5,1.27; 6 -4.5,0; 7 -4.5,-1.27; 8 -4.5,-2.54; 14 4.5,-2.54; 15 4.5,-1.27; 16 4.5,0; 17 4.5,1.27; 18 4.5,2.54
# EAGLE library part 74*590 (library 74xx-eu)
8-bit binary COUNTER, output register

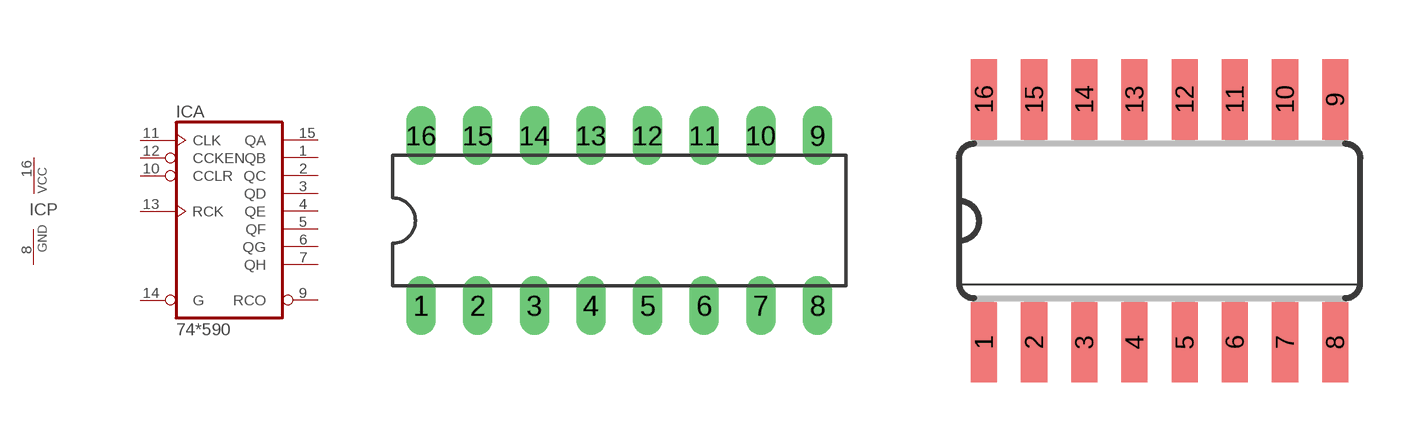
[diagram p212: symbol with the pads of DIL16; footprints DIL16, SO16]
Designator prefix IC; gates A=74590 P=PWRN

## 74AC590N, 74ACT590N, 74HC590N, 74LS590N  [DIL16]
1  A:QB  hiz
2  A:QC  hiz
3  A:QD  hiz
4  A:QE  hiz
5  A:QF  hiz
6  A:QG  hiz
7  A:QH  hiz
8  P:GND  pwr
9  A:RCO  out
10  A:CCLR  in
11  A:CLK  in
12  A:CCKEN  in
13  A:RCK  in
14  A:G  in
15  A:QA  hiz
16  P:VCC  pwr

## 74AC590D, 74HC590D, 74LS590D  [SO16]
Pads as for DIL16

## 74AC590FK, 74HC590FK, 74LS590FK  [LCC20]
2  A:QB  hiz
3  A:QC  hiz
4  A:QD  hiz
5  A:QE  hiz
7  A:QF  hiz
8  A:QG  hiz
9  A:QH  hiz
10  P:GND  pwr
12  A:RCO  out
13  A:CCLR  in
14  A:CLK  in
15  A:CCKEN  in
17  A:RCK  in
18  A:G  in
19  A:QA  hiz
20  P:VCC  pwr

## Footprint DIL16 (pad centres in mm)
Dual In Line Package
drill 0.813 long: 1 -8.89,-3.81; 2 -6.35,-3.81; 3 -3.81,-3.81; 4 -1.27,-3.81; 5 1.27,-3.81; 6 3.81,-3.81; 7 6.35,-3.81; 8 8.89,-3.81; 9 8.89,3.81; 10 6.35,3.81; 11 3.81,3.81; 12 1.27,3.81; 13 -1.27,3.81; 14 -3.81,3.81; 15 -6.35,3.81; 16 -8.89,3.81

## Footprint SO16 (pad centres in mm)
Small Outline package 150 mil
smd 0.66 x 2.032: 1 -4.445,-3.073; 2 -3.175,-3.073; 3 -1.905,-3.073; 4 -0.635,-3.073; 5 0.635,-3.073; 6 1.905,-3.073; 7 3.175,-3.073; 8 4.445,-3.073; 9 4.445,3.073; 10 3.175,3.073; 11 1.905,3.073; 12 0.635,3.073; 13 -0.635,3.073; 14 -1.905,3.073; 15 -3.175,3.073; 16 -4.445,3.073

## Footprint LCC20 (pad centres in mm)
Leadless Chip Carrier Ceramic Package
smd 0.8 x 3.4: 1 0,3.8
smd 0.8 x 2: 2 -1.27,4.5; 3 -2.54,4.5; 9 -2.54,-4.5; 10 -1.27,-4.5; 11 0,-4.5; 12 1.27,-4.5; 13 2.54,-4.5; 19 2.54,4.5; 20 1.27,4.5
smd 2 x 0.8: 4 -4.5,2.54; 5 -4.5,1.27; 6 -4.5,0; 7 -4.5,-1.27; 8 -4.5,-2.54; 14 4.5,-2.54; 15 4.5,-1.27; 16 4.5,0; 17 4.5,1.27; 18 4.5,2.54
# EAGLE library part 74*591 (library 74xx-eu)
8-bit binary COUNTER, output register

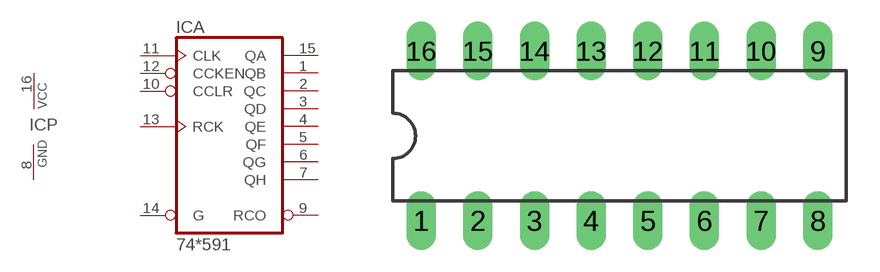
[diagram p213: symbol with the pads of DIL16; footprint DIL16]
Designator prefix IC; gates A=74591 P=PWRN

## 74591N  [DIL16]
1  A:QB  oc
2  A:QC  oc
3  A:QD  oc
4  A:QE  oc
5  A:QF  oc
6  A:QG  oc
7  A:QH  oc
8  P:GND  pwr
9  A:RCO  out
10  A:CCLR  in
11  A:CLK  in
12  A:CCKEN  in
13  A:RCK  in
14  A:G  in
15  A:QA  oc
16  P:VCC  pwr

## Footprint DIL16 (pad centres in mm)
Dual In Line Package
drill 0.813 long: 1 -8.89,-3.81; 2 -6.35,-3.81; 3 -3.81,-3.81; 4 -1.27,-3.81; 5 1.27,-3.81; 6 3.81,-3.81; 7 6.35,-3.81; 8 8.89,-3.81; 9 8.89,3.81; 10 6.35,3.81; 11 3.81,3.81; 12 1.27,3.81; 13 -1.27,3.81; 14 -3.81,3.81; 15 -6.35,3.81; 16 -8.89,3.81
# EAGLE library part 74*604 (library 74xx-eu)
Octal 2-input MULTIPLEXED LATCH

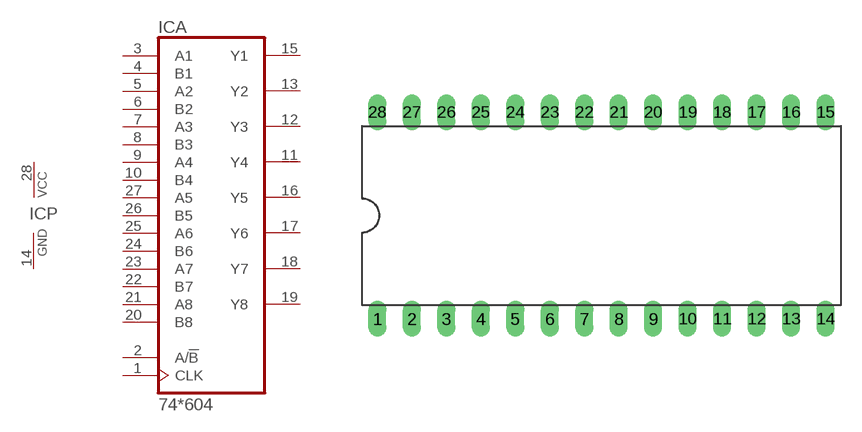
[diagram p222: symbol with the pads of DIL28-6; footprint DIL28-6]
Designator prefix IC; gates A=74604 P=PWRN

## 74604N  [DIL28-6]
1  A:CLK  in
2  A:A/!B  in
3  A:A1  in
4  A:B1  in
5  A:A2  in
6  A:B2  in
7  A:A3  in
8  A:B3  in
9  A:A4  in
10  A:B4  in
11  A:Y4  hiz
12  A:Y3  hiz
13  A:Y2  hiz
14  P:GND  pwr
15  A:Y1  hiz
16  A:Y5  hiz
17  A:Y6  hiz
18  A:Y7  hiz
19  A:Y8  hiz
20  A:B8  in
21  A:A8  in
22  A:B7  in
23  A:A7  in
24  A:B6  in
25  A:A6  in
26  A:B5  in
27  A:A5  in
28  P:VCC  pwr

## Footprint DIL28-6 (pad centres in mm)
Dual In Line Package 0.6 inch
drill 0.813 long: 1 -16.51,-7.62; 2 -13.97,-7.62; 3 -11.43,-7.62; 4 -8.89,-7.62; 5 -6.35,-7.62; 6 -3.81,-7.62; 7 -1.27,-7.62; 8 1.27,-7.62; 9 3.81,-7.62; 10 6.35,-7.62; 11 8.89,-7.62; 12 11.43,-7.62; 13 13.97,-7.62; 14 16.51,-7.62; 15 16.51,7.62; 16 13.97,7.62; 17 11.43,7.62; 18 8.89,7.62; 19 6.35,7.62; 20 3.81,7.62; 21 1.27,7.62; 22 -1.27,7.62; 23 -3.81,7.62; 24 -6.35,7.62; 25 -8.89,7.62; 26 -11.43,7.62; 27 -13.97,7.62; 28 -16.51,7.62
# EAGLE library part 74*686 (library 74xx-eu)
8-bit MAGNITUDE/IDENTITY COMPARATOR, totem pole

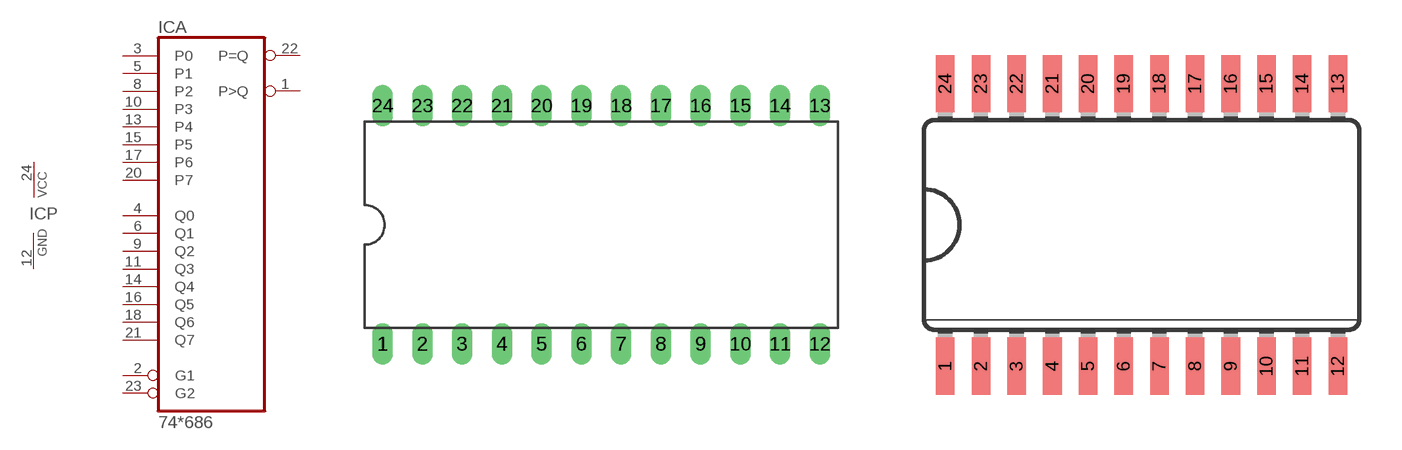
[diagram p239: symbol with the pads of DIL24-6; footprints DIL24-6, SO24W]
Designator prefix IC; gates A=74686 P=PWRN

## 74LS686N  [DIL24-6]
1  A:P>Q  out
2  A:G1  in
3  A:P0  in
4  A:Q0  in
5  A:P1  in
6  A:Q1  in
8  A:P2  in
9  A:Q2  in
10  A:P3  in
11  A:Q3  in
12  P:GND  pwr
13  A:P4  in
14  A:Q4  in
15  A:P5  in
16  A:Q5  in
17  A:P6  in
18  A:Q6  in
20  A:P7  in
21  A:Q7  in
22  A:P=Q  out
23  A:G2  in
24  P:VCC  pwr

## 74LS686DW  [SO24W]
Pads as for DIL24-6

## 74LS686FK  [LCC28]
2  A:P>Q  out
3  A:G1  in
4  A:P0  in
5  A:Q0  in
6  A:P1  in
7  A:Q1  in
10  A:P2  in
11  A:Q2  in
12  A:P3  in
13  A:Q3  in
14  P:GND  pwr
16  A:P4  in
17  A:Q4  in
18  A:P5  in
19  A:Q5  in
20  A:P6  in
21  A:Q6  in
24  A:P7  in
25  A:Q7  in
26  A:P=Q  out
27  A:G2  in
28  P:VCC  pwr

## Footprint DIL24-6 (pad centres in mm)
Dual In Line Package 0.6 inch
drill 0.813 long: 1 -13.97,-7.62; 2 -11.43,-7.62; 3 -8.89,-7.62; 4 -6.35,-7.62; 5 -3.81,-7.62; 6 -1.27,-7.62; 7 1.27,-7.62; 8 3.81,-7.62; 9 6.35,-7.62; 10 8.89,-7.62; 11 11.43,-7.62; 12 13.97,-7.62; 13 13.97,7.62; 14 11.43,7.62; 15 8.89,7.62; 16 6.35,7.62; 17 3.81,7.62; 18 1.27,7.62; 19 -1.27,7.62; 20 -3.81,7.62; 21 -6.35,7.62; 22 -8.89,7.62; 23 -11.43,7.62; 24 -13.97,7.62

## Footprint SO24W (pad centres in mm)
Wide Small Outline package 300 mil
smd 0.66 x 2.032: 1 -6.985,-5.029; 2 -5.715,-5.029; 3 -4.445,-5.029; 4 -3.175,-5.029; 5 -1.905,-5.029; 6 -0.635,-5.029; 7 0.635,-5.029; 8 1.905,-5.029; 9 3.175,-5.029; 10 4.445,-5.029; 11 5.715,-5.029; 12 6.985,-5.029; 13 6.985,5.029; 14 5.715,5.029; 15 4.445,5.029; 16 3.175,5.029; 17 1.905,5.029; 18 0.635,5.029; 19 -0.635,5.029; 20 -1.905,5.029; 21 -3.175,5.029; 22 -4.445,5.029; 23 -5.715,5.029; 24 -6.985,5.029

## Footprint LCC28 (pad centres in mm)
Leadless Chip Carrier Ceramic Package
smd 0.8 x 3.4: 1 0,5.1
smd 0.8 x 2: 2 -1.27,5.8; 3 -2.54,5.8; 4 -3.81,5.8; 12 -3.81,-5.8; 13 -2.54,-5.8; 14 -1.27,-5.8; 15 0,-5.8; 16 1.27,-5.8; 17 2.54,-5.8; 18 3.81,-5.8; 26 3.81,5.8; 27 2.54,5.8; 28 1.27,5.8
smd 2 x 0.8: 5 -5.8,3.81; 6 -5.8,2.54; 7 -5.8,1.27; 8 -5.8,0; 9 -5.8,-1.27; 10 -5.8,-2.54; 11 -5.8,-3.81; 19 5.8,-3.81; 20 5.8,-2.54; 21 5.8,-1.27; 22 5.8,0; 23 5.8,1.27; 24 5.8,2.54; 25 5.8,3.81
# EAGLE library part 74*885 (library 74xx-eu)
Expandable 8-bit magnitude COMPARATOR

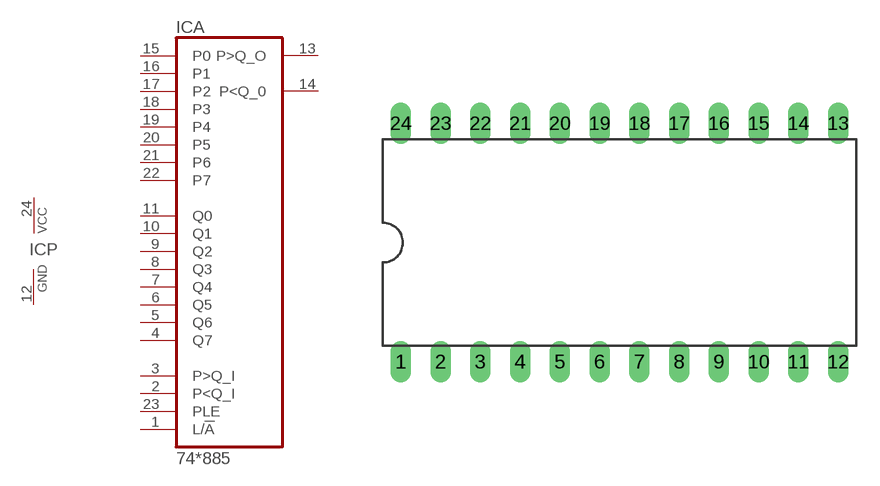
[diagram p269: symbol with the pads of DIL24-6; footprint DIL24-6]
Designator prefix IC; gates A=74885 P=PWRN

## 74AS885NT  [DIL24-6]
1  A:L/!A  in
2  A:P<Q_I  in
3  A:P>Q_I  in
4  A:Q7  in
5  A:Q6  in
6  A:Q5  in
7  A:Q4  in
8  A:Q3  in
9  A:Q2  in
10  A:Q1  in
11  A:Q0  in
12  P:GND  pwr
13  A:P>Q_O  out
14  A:P<Q_0  out
15  A:P0  in
16  A:P1  in
17  A:P2  in
18  A:P3  in
19  A:P4  in
20  A:P5  in
21  A:P6  in
22  A:P7  in
23  A:PLE  in
24  P:VCC  pwr

## Footprint DIL24-6 (pad centres in mm)
Dual In Line Package 0.6 inch
drill 0.813 long: 1 -13.97,-7.62; 2 -11.43,-7.62; 3 -8.89,-7.62; 4 -6.35,-7.62; 5 -3.81,-7.62; 6 -1.27,-7.62; 7 1.27,-7.62; 8 3.81,-7.62; 9 6.35,-7.62; 10 8.89,-7.62; 11 11.43,-7.62; 12 13.97,-7.62; 13 13.97,7.62; 14 11.43,7.62; 15 8.89,7.62; 16 6.35,7.62; 17 3.81,7.62; 18 1.27,7.62; 19 -1.27,7.62; 20 -3.81,7.62; 21 -6.35,7.62; 22 -8.89,7.62; 23 -11.43,7.62; 24 -13.97,7.62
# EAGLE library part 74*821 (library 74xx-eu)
10-bit bus interface FLIP FLOP

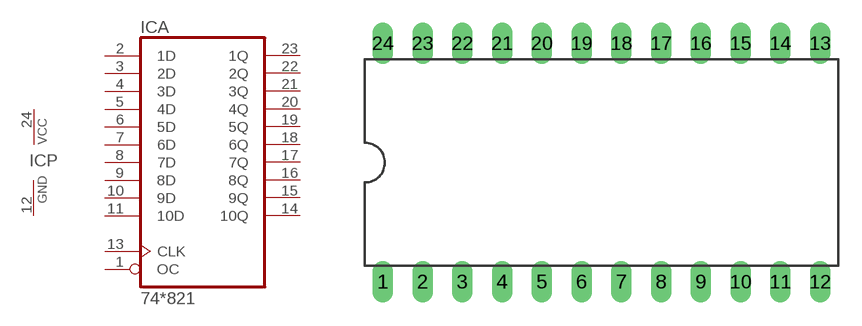
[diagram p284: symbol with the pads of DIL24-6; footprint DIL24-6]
Designator prefix IC; gates A=74821 P=PWRN

## 74AC821NT, 74ACT821NT, 74AS821NT  [DIL24-6]
1  A:OC  in
2  A:1D  in
3  A:2D  in
4  A:3D  in
5  A:4D  in
6  A:5D  in
7  A:6D  in
8  A:7D  in
9  A:8D  in
10  A:9D  in
11  A:10D  in
12  P:GND  pwr
13  A:CLK  in
14  A:10Q  hiz
15  A:9Q  hiz
16  A:8Q  hiz
17  A:7Q  hiz
18  A:6Q  hiz
19  A:5Q  hiz
20  A:4Q  hiz
21  A:3Q  hiz
22  A:2Q  hiz
23  A:1Q  hiz
24  P:VCC  pwr

## Footprint DIL24-6 (pad centres in mm)
Dual In Line Package 0.6 inch
drill 0.813 long: 1 -13.97,-7.62; 2 -11.43,-7.62; 3 -8.89,-7.62; 4 -6.35,-7.62; 5 -3.81,-7.62; 6 -1.27,-7.62; 7 1.27,-7.62; 8 3.81,-7.62; 9 6.35,-7.62; 10 8.89,-7.62; 11 11.43,-7.62; 12 13.97,-7.62; 13 13.97,7.62; 14 11.43,7.62; 15 8.89,7.62; 16 6.35,7.62; 17 3.81,7.62; 18 1.27,7.62; 19 -1.27,7.62; 20 -3.81,7.62; 21 -6.35,7.62; 22 -8.89,7.62; 23 -11.43,7.62; 24 -13.97,7.62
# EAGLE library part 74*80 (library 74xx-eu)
1-bit full ADDER,, parallel carry

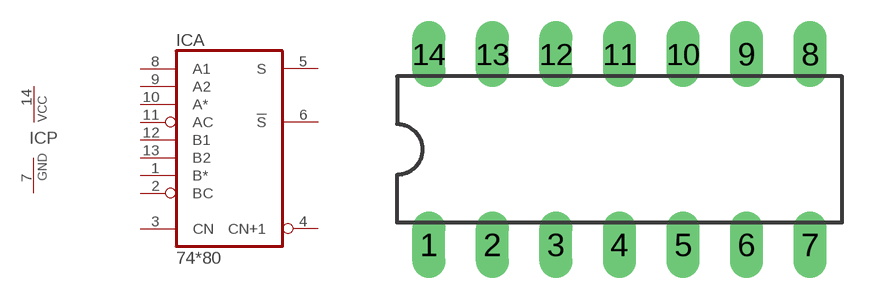
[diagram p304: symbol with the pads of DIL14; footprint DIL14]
Designator prefix IC; gates A=7480 P=PWRN

## 7480N  [DIL14]
1  A:B*
2  A:BC  in
3  A:CN  in
4  A:CN+1  out
5  A:S  out
6  A:!S  out
7  P:GND  pwr
8  A:A1  in
9  A:A2  in
10  A:A*
11  A:AC  in
12  A:B1  in
13  A:B2  in
14  P:VCC  pwr

## Footprint DIL14 (pad centres in mm)
Dual In Line Package
drill 0.813 long: 1 -7.62,-3.81; 2 -5.08,-3.81; 3 -2.54,-3.81; 4 0,-3.81; 5 2.54,-3.81; 6 5.08,-3.81; 7 7.62,-3.81; 8 7.62,3.81; 9 5.08,3.81; 10 2.54,3.81; 11 0,3.81; 12 -2.54,3.81; 13 -5.08,3.81; 14 -7.62,3.81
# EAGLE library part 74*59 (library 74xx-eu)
Devide by-N-Counter 74HC/HCT4059 Source: www.standardics.nxp.com/products/hc/datasheet/74hc4059.pdf

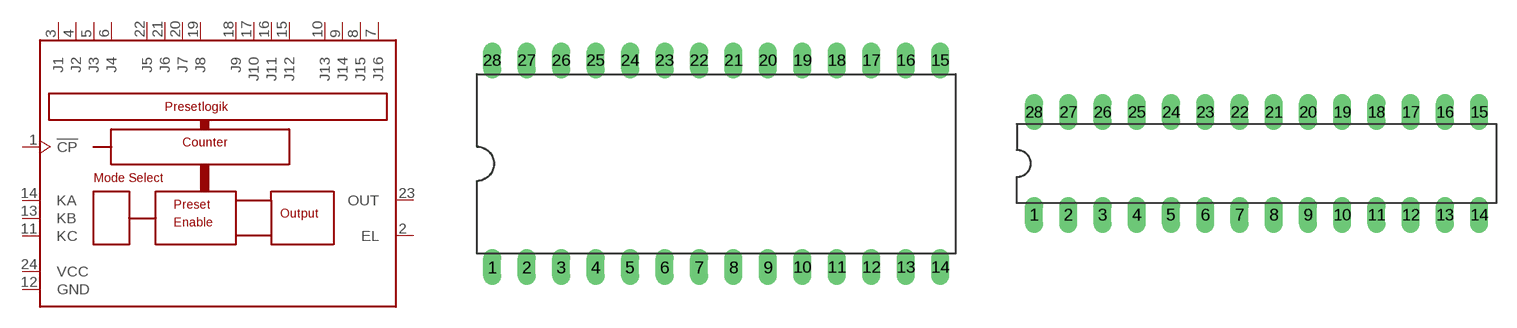
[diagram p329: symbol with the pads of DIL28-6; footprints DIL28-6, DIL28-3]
Designator prefix IC

## 74HC59N, 74HCT59N  [DIL28-6]
1  !CP  in
2  EL  in
3  J1  in
4  J2  in
5  J3  in
6  J4  in
7  J16  in
8  J15  in
9  J14  in
10  J13  in
11  KC  in
12  GND  pwr
13  KB  in
14  KA  in
15  J12  in
16  J11  in
17  J10  in
18  J9  in
19  J8  in
20  J7  in
21  J6  in
22  J5  in
23  OUT  out
24  VCC  pwr

## 74HC59N3, 74HCT59N3  [DIL28-3]
Pads as for DIL28-6

## 74HC59D, 74HCT59D  [SO24W]
Pads as for DIL28-6

## Footprint DIL28-6 (pad centres in mm)
Dual In Line Package 0.6 inch
drill 0.813 long: 1 -16.51,-7.62; 2 -13.97,-7.62; 3 -11.43,-7.62; 4 -8.89,-7.62; 5 -6.35,-7.62; 6 -3.81,-7.62; 7 -1.27,-7.62; 8 1.27,-7.62; 9 3.81,-7.62; 10 6.35,-7.62; 11 8.89,-7.62; 12 11.43,-7.62; 13 13.97,-7.62; 14 16.51,-7.62; 15 16.51,7.62; 16 13.97,7.62; 17 11.43,7.62; 18 8.89,7.62; 19 6.35,7.62; 20 3.81,7.62; 21 1.27,7.62; 22 -1.27,7.62; 23 -3.81,7.62; 24 -6.35,7.62; 25 -8.89,7.62; 26 -11.43,7.62; 27 -13.97,7.62; 28 -16.51,7.62

## Footprint DIL28-3 (pad centres in mm)
Dual In Line Package Small
drill 0.813 long: 1 -16.51,-3.81; 2 -13.97,-3.81; 3 -11.43,-3.81; 4 -8.89,-3.81; 5 -6.35,-3.81; 6 -3.81,-3.81; 7 -1.27,-3.81; 8 1.27,-3.81; 9 3.81,-3.81; 10 6.35,-3.81; 11 8.89,-3.81; 12 11.43,-3.81; 13 13.97,-3.81; 14 16.51,-3.81; 15 16.51,3.81; 16 13.97,3.81; 17 11.43,3.81; 18 8.89,3.81; 19 6.35,3.81; 20 3.81,3.81; 21 1.27,3.81; 22 -1.27,3.81; 23 -3.81,3.81; 24 -6.35,3.81; 25 -8.89,3.81; 26 -11.43,3.81; 27 -13.97,3.81; 28 -16.51,3.81

## Footprint SO24W (pad centres in mm)
Wide Small Outline package 300 mil
smd 0.66 x 2.032: 1 -6.985,-5.029; 2 -5.715,-5.029; 3 -4.445,-5.029; 4 -3.175,-5.029; 5 -1.905,-5.029; 6 -0.635,-5.029; 7 0.635,-5.029; 8 1.905,-5.029; 9 3.175,-5.029; 10 4.445,-5.029; 11 5.715,-5.029; 12 6.985,-5.029; 13 6.985,5.029; 14 5.715,5.029; 15 4.445,5.029; 16 3.175,5.029; 17 1.905,5.029; 18 0.635,5.029; 19 -0.635,5.029; 20 -1.905,5.029; 21 -3.175,5.029; 22 -4.445,5.029; 23 -5.715,5.029; 24 -6.985,5.029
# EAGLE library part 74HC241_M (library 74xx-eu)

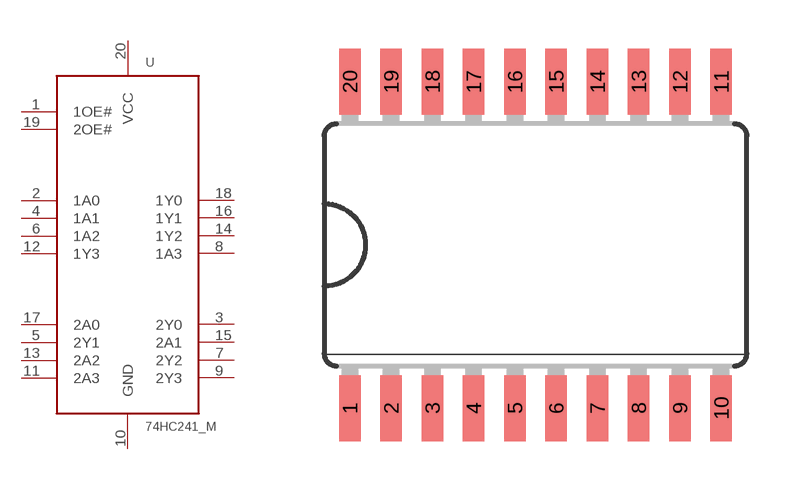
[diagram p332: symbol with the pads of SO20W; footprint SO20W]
Designator prefix -

## 74HC241_M  [SO20W]
1  1OE#  in
2  1A0  in
3  2Y0  out
4  1A1  in
5  2Y1  out
6  1A2  in
7  2Y2  out
8  1A3  in
9  2Y3  out
10  GND  in
11  2A3  in
12  1Y3  out
13  2A2  in
14  1Y2  out
15  2A1  in
16  1Y1  out
17  2A0  in
18  1Y0  out
19  2OE#  in
20  VCC  in

## Footprint SO20W (pad centres in mm)
Wide Small Outline package 300 mil
smd 0.66 x 2.032: 1 -5.715,-5.029; 2 -4.445,-5.029; 3 -3.175,-5.029; 4 -1.905,-5.029; 5 -0.635,-5.029; 6 0.635,-5.029; 7 1.905,-5.029; 8 3.175,-5.029; 9 4.445,-5.029; 10 5.715,-5.029; 11 5.715,5.029; 12 4.445,5.029; 13 3.175,5.029; 14 1.905,5.029; 15 0.635,5.029; 16 -0.635,5.029; 17 -1.905,5.029; 18 -3.175,5.029; 19 -4.445,5.029; 20 -5.715,5.029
